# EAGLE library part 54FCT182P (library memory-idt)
MEMORY

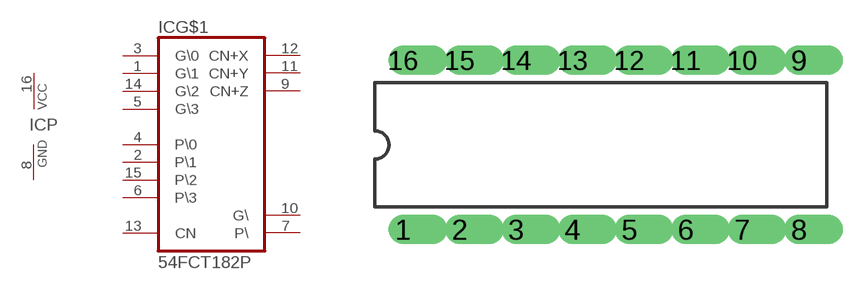
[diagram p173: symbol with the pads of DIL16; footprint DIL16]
Designator prefix IC; gates G$1=182 P=VCCGND

## 54FCT182P  [DIL16]
1  G$1:G\1  in
2  G$1:P\1  in
3  G$1:G\0  in
4  G$1:P\0  in
5  G$1:G\3  in
6  G$1:P\3  in
7  G$1:P\  out
8  P:GND  pwr
9  G$1:CN+Z  out
10  G$1:G\  out
11  G$1:CN+Y  out
12  G$1:CN+X  out
13  G$1:CN  in
14  G$1:G\2  in
15  G$1:P\2  in
16  P:VCC  pwr

## Footprint DIL16 (pad centres in mm)
Dual In Line
drill 0.813 offset: 1 -8.89,-3.81; 2 -6.35,-3.81; 3 -3.81,-3.81; 4 -1.27,-3.81; 5 1.27,-3.81; 6 3.81,-3.81; 7 6.35,-3.81; 8 8.89,-3.81; 9 8.89,3.81; 10 6.35,3.81; 11 3.81,3.81; 12 1.27,3.81; 13 -1.27,3.81; 14 -3.81,3.81; 15 -6.35,3.81; 16 -8.89,3.81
